VERSION 5.8 ;
BUSBITCHARS "[]" ;
DIVIDERCHAR "/" ;
UNITS
    DATABASE MICRONS 1000 ;
END UNITS

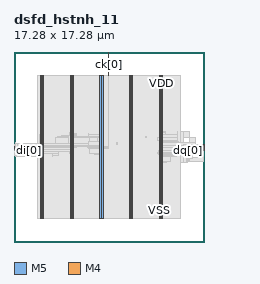
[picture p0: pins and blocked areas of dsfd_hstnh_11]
MACRO dsfd_hstnh_11
  FOREIGN dsfd_hstnh_11 0 0 ;
  CLASS BLOCK ;
  SIZE 17.28 BY 17.28 ;
  PIN ck[0]
    DIRECTION INPUT ;
    USE SIGNAL ;
    PORT
      LAYER M5 ;
        RECT  8.592 17.196 8.616 17.28 ;
    END
    PORT
      LAYER M5 ;
        RECT  8.592 15.143 8.616 17.232 ;
    END
  END ck[0]
  PIN di[0]
    DIRECTION INPUT ;
    USE SIGNAL ;
    PORT
      LAYER M4 ;
        RECT  0 8.352 0.084 8.376 ;
    END
  END di[0]
  PIN di[10]
    DIRECTION INPUT ;
    USE SIGNAL ;
    PORT
      LAYER M4 ;
        RECT  0 8.832 0.084 8.856 ;
    END
  END di[10]
  PIN di[1]
    DIRECTION INPUT ;
    USE SIGNAL ;
    PORT
      LAYER M4 ;
        RECT  0 8.4 0.084 8.424 ;
    END
  END di[1]
  PIN di[2]
    DIRECTION INPUT ;
    USE SIGNAL ;
    PORT
      LAYER M4 ;
        RECT  0 8.448 0.084 8.472 ;
    END
  END di[2]
  PIN di[3]
    DIRECTION INPUT ;
    USE SIGNAL ;
    PORT
      LAYER M4 ;
        RECT  0 8.496 0.084 8.52 ;
    END
  END di[3]
  PIN di[4]
    DIRECTION INPUT ;
    USE SIGNAL ;
    PORT
      LAYER M4 ;
        RECT  0 8.544 0.084 8.568 ;
    END
  END di[4]
  PIN di[5]
    DIRECTION INPUT ;
    USE SIGNAL ;
    PORT
      LAYER M4 ;
        RECT  0 8.592 0.084 8.616 ;
    END
  END di[5]
  PIN di[6]
    DIRECTION INPUT ;
    USE SIGNAL ;
    PORT
      LAYER M4 ;
        RECT  0 8.64 0.084 8.664 ;
    END
  END di[6]
  PIN di[7]
    DIRECTION INPUT ;
    USE SIGNAL ;
    PORT
      LAYER M4 ;
        RECT  0 8.688 0.084 8.712 ;
    END
  END di[7]
  PIN di[8]
    DIRECTION INPUT ;
    USE SIGNAL ;
    PORT
      LAYER M4 ;
        RECT  0 8.736 0.084 8.76 ;
    END
  END di[8]
  PIN di[9]
    DIRECTION INPUT ;
    USE SIGNAL ;
    PORT
      LAYER M4 ;
        RECT  0 8.784 0.084 8.808 ;
    END
  END di[9]
  PIN dq[0]
    DIRECTION OUTPUT ;
    USE SIGNAL ;
    PORT
      LAYER M4 ;
        RECT  17.196 8.352 17.28 8.376 ;
    END
  END dq[0]
  PIN dq[10]
    DIRECTION OUTPUT ;
    USE SIGNAL ;
    PORT
      LAYER M4 ;
        RECT  17.196 8.832 17.28 8.856 ;
    END
  END dq[10]
  PIN dq[1]
    DIRECTION OUTPUT ;
    USE SIGNAL ;
    PORT
      LAYER M4 ;
        RECT  17.196 8.4 17.28 8.424 ;
    END
  END dq[1]
  PIN dq[2]
    DIRECTION OUTPUT ;
    USE SIGNAL ;
    PORT
      LAYER M4 ;
        RECT  17.196 8.448 17.28 8.472 ;
    END
  END dq[2]
  PIN dq[3]
    DIRECTION OUTPUT ;
    USE SIGNAL ;
    PORT
      LAYER M4 ;
        RECT  17.196 8.496 17.28 8.52 ;
    END
  END dq[3]
  PIN dq[4]
    DIRECTION OUTPUT ;
    USE SIGNAL ;
    PORT
      LAYER M4 ;
        RECT  17.196 8.544 17.28 8.568 ;
    END
  END dq[4]
  PIN dq[5]
    DIRECTION OUTPUT ;
    USE SIGNAL ;
    PORT
      LAYER M4 ;
        RECT  17.196 8.592 17.28 8.616 ;
    END
  END dq[5]
  PIN dq[6]
    DIRECTION OUTPUT ;
    USE SIGNAL ;
    PORT
      LAYER M4 ;
        RECT  17.196 8.64 17.28 8.664 ;
    END
  END dq[6]
  PIN dq[7]
    DIRECTION OUTPUT ;
    USE SIGNAL ;
    PORT
      LAYER M4 ;
        RECT  17.196 8.688 17.28 8.712 ;
    END
  END dq[7]
  PIN dq[8]
    DIRECTION OUTPUT ;
    USE SIGNAL ;
    PORT
      LAYER M4 ;
        RECT  17.196 8.736 17.28 8.76 ;
    END
  END dq[8]
  PIN dq[9]
    DIRECTION OUTPUT ;
    USE SIGNAL ;
    PORT
      LAYER M4 ;
        RECT  17.196 8.784 17.28 8.808 ;
    END
  END dq[9]
  PIN VDD
    DIRECTION INOUT ;
    USE POWER ;
    PORT
      LAYER M5 ;
        RECT  13.392 2.151 13.512 15.129 ;
        RECT  10.692 2.151 10.812 15.129 ;
        RECT  7.992 2.151 8.112 15.129 ;
        RECT  5.292 2.151 5.412 15.129 ;
        RECT  2.592 2.151 2.712 15.129 ;
    END
  END VDD
  PIN VSS
    DIRECTION INOUT ;
    USE GROUND ;
    PORT
      LAYER M5 ;
        RECT  13.2 2.137 13.32 15.143 ;
        RECT  10.5 2.137 10.62 15.143 ;
        RECT  7.8 2.137 7.92 15.143 ;
        RECT  5.1 2.137 5.22 15.143 ;
        RECT  2.4 2.137 2.52 15.143 ;
    END
  END VSS
  # OT_OBS_CLOSED layer=M5 d_um=1.536 added=0
  OBS
    LAYER RVTN ;
     RECT  2.16 2.16 15.12 2.295 ;
     RECT  2.16 2.565 15.12 2.835 ;
     RECT  2.16 3.105 15.12 3.375 ;
     RECT  2.16 3.645 15.12 3.915 ;
     RECT  2.16 4.185 15.12 4.455 ;
     RECT  2.16 4.725 15.12 4.995 ;
     RECT  2.16 5.265 15.12 5.535 ;
     RECT  2.16 5.805 15.12 6.075 ;
     RECT  2.16 6.345 15.12 6.615 ;
     RECT  2.16 6.885 15.12 7.155 ;
     RECT  2.16 7.425 15.12 7.695 ;
     RECT  2.16 7.965 15.12 8.235 ;
     RECT  2.16 8.505 15.12 8.775 ;
     RECT  2.16 9.045 15.12 9.315 ;
     RECT  2.16 9.585 15.12 9.855 ;
     RECT  2.16 10.125 15.12 10.395 ;
     RECT  2.16 10.665 15.12 10.935 ;
     RECT  2.16 11.205 15.12 11.475 ;
     RECT  2.16 11.745 15.12 12.015 ;
     RECT  2.16 12.285 15.12 12.555 ;
     RECT  2.16 12.825 15.12 13.095 ;
     RECT  2.16 13.365 15.12 13.635 ;
     RECT  2.16 13.905 15.12 14.175 ;
     RECT  2.16 14.445 15.12 14.715 ;
     RECT  2.16 14.985 15.12 15.12 ;
    LAYER RVTP ;
     RECT  2.16 2.295 15.12 2.565 ;
     RECT  2.16 2.835 15.12 3.105 ;
     RECT  2.16 3.375 15.12 3.645 ;
     RECT  2.16 3.915 15.12 4.185 ;
     RECT  2.16 4.455 15.12 4.725 ;
     RECT  2.16 4.995 15.12 5.265 ;
     RECT  2.16 5.535 15.12 5.805 ;
     RECT  2.16 6.075 15.12 6.345 ;
     RECT  2.16 6.615 15.12 6.885 ;
     RECT  2.16 7.155 15.12 7.425 ;
     RECT  2.16 7.695 15.12 7.965 ;
     RECT  2.16 8.235 15.12 8.505 ;
     RECT  2.16 8.775 15.12 9.045 ;
     RECT  2.16 9.315 15.12 9.585 ;
     RECT  2.16 9.855 15.12 10.125 ;
     RECT  2.16 10.395 15.12 10.665 ;
     RECT  2.16 10.935 15.12 11.205 ;
     RECT  2.16 11.475 15.12 11.745 ;
     RECT  2.16 12.015 15.12 12.285 ;
     RECT  2.16 12.555 15.12 12.825 ;
     RECT  2.16 13.095 15.12 13.365 ;
     RECT  2.16 13.635 15.12 13.905 ;
     RECT  2.16 14.175 15.12 14.445 ;
     RECT  2.16 14.715 15.12 14.985 ;
    LAYER M1 ;
     RECT  2.16 2.151 15.12 15.129 ;
    LAYER M2 ;
     RECT  0.031 7.902 0.103 7.92 ;
     RECT  0.103 7.902 0.139 7.956 ;
     RECT  0.139 7.902 0.175 8.46 ;
     RECT  0.175 7.776 2.16 8.46 ;
     RECT  2.16 2.151 15.12 15.129 ;
     RECT  15.12 7.236 15.431 10.044 ;
     RECT  15.431 7.236 15.755 8.532 ;
     RECT  15.755 7.326 15.899 8.532 ;
     RECT  15.899 7.326 15.971 8.46 ;
     RECT  15.431 9.486 15.971 10.044 ;
     RECT  15.971 8.406 16.007 8.46 ;
     RECT  16.007 8.442 16.079 8.46 ;
     RECT  15.971 9.486 16.511 9.504 ;
     RECT  15.971 7.326 17.231 7.65 ;
     RECT  17.231 7.326 17.267 7.344 ;
     RECT  17.095 8.586 17.267 8.604 ;
    LAYER M3 ;
     RECT  2.415 2.143 2.505 2.413 ;
     RECT  5.115 2.143 5.205 2.413 ;
     RECT  7.815 2.143 7.905 2.413 ;
     RECT  10.515 2.143 10.605 2.413 ;
     RECT  13.215 2.143 13.305 2.413 ;
     RECT  13.215 2.413 13.497 7.195 ;
     RECT  13.215 7.195 13.878 7.321 ;
     RECT  15.732 7.231 15.75 7.591 ;
     RECT  17.244 7.321 17.262 7.627 ;
     RECT  13.215 7.321 14.274 7.735 ;
     RECT  3.492 7.771 3.51 7.861 ;
     RECT  13.215 7.735 14.778 7.889 ;
     RECT  0.18 7.771 0.198 7.897 ;
     RECT  13.215 7.889 14.382 7.933 ;
     RECT  7.815 2.413 8.097 7.969 ;
     RECT  2.415 2.413 2.697 8.041 ;
     RECT  3.492 7.861 4.086 8.041 ;
     RECT  5.115 2.413 5.397 8.041 ;
     RECT  7.308 7.969 8.097 8.041 ;
     RECT  13.176 7.933 14.382 8.041 ;
     RECT  0.036 7.897 0.198 8.059 ;
     RECT  17.208 7.627 17.262 8.155 ;
     RECT  13.068 8.041 14.382 8.159 ;
     RECT  0.036 8.059 0.27 8.189 ;
     RECT  2.415 8.041 4.086 8.203 ;
     RECT  5.004 8.041 5.397 8.203 ;
     RECT  0.108 8.189 0.27 8.285 ;
     RECT  15.732 7.591 16.254 8.311 ;
     RECT  13.176 8.159 14.382 8.339 ;
     RECT  2.415 8.203 5.397 8.395 ;
     RECT  6.876 8.041 8.097 8.473 ;
     RECT  6.84 8.473 8.097 8.509 ;
     RECT  0.144 8.285 0.27 8.525 ;
     RECT  6.84 8.509 8.586 8.545 ;
     RECT  2.376 8.395 5.397 8.581 ;
     RECT  6.804 8.545 8.586 8.581 ;
     RECT  2.376 8.581 5.706 8.587 ;
     RECT  17.1 8.155 17.262 8.609 ;
     RECT  17.1 8.609 17.118 8.621 ;
     RECT  2.304 8.587 5.706 8.635 ;
     RECT  13.215 8.339 14.382 8.635 ;
     RECT  15.408 8.311 16.254 8.635 ;
     RECT  6.66 8.581 8.586 8.699 ;
     RECT  2.232 8.635 5.706 8.707 ;
     RECT  6.66 8.699 6.822 8.707 ;
     RECT  13.215 8.635 16.254 8.731 ;
     RECT  2.232 8.707 6.822 8.807 ;
     RECT  2.304 8.807 6.822 8.969 ;
     RECT  9.36 8.851 9.45 8.969 ;
     RECT  0.144 8.525 0.162 9.005 ;
     RECT  9.36 8.969 9.378 9.005 ;
     RECT  13.215 8.731 16.506 9.041 ;
     RECT  13.215 9.041 14.994 9.113 ;
     RECT  13.215 9.113 14.85 9.211 ;
     RECT  3.78 8.969 6.822 9.481 ;
     RECT  7.56 8.699 8.406 9.481 ;
     RECT  3.78 9.481 8.406 9.509 ;
     RECT  13.032 9.211 14.85 9.509 ;
     RECT  15.948 9.041 16.506 9.509 ;
     RECT  3.96 9.509 8.406 9.517 ;
     RECT  3.96 9.517 8.478 9.617 ;
     RECT  11.988 9.517 12.006 9.617 ;
     RECT  4.32 9.617 5.67 9.689 ;
     RECT  2.304 8.969 2.697 9.779 ;
     RECT  6.768 9.617 8.097 9.779 ;
     RECT  13.215 9.509 14.85 9.779 ;
     RECT  5.004 9.689 5.67 9.815 ;
     RECT  7.56 9.779 8.097 9.815 ;
     RECT  5.076 9.815 5.67 9.851 ;
     RECT  6.768 9.779 6.786 9.887 ;
     RECT  5.076 9.851 5.397 9.959 ;
     RECT  13.215 9.779 13.806 9.959 ;
     RECT  13.215 9.959 13.77 10.049 ;
     RECT  15.948 9.509 15.966 10.049 ;
     RECT  14.832 9.779 14.85 10.085 ;
     RECT  2.415 9.779 2.697 14.867 ;
     RECT  5.115 9.959 5.397 14.867 ;
     RECT  7.815 9.815 8.097 14.867 ;
     RECT  10.515 2.413 10.797 14.867 ;
     RECT  13.215 10.049 13.497 14.867 ;
     RECT  2.415 14.867 2.505 15.137 ;
     RECT  5.115 14.867 5.205 15.137 ;
     RECT  7.815 14.867 7.905 15.137 ;
     RECT  10.515 14.867 10.605 15.137 ;
     RECT  13.215 14.867 13.305 15.137 ;
    LAYER M4 ;
     RECT  0.025 8.16 0.06 8.184 ;
     RECT  0.06 8.16 0.133 8.856 ;
     RECT  0.133 8.16 0.169 9 ;
     RECT  0.169 8.064 0.281 9 ;
     RECT  0.281 8.4 2.408 9 ;
     RECT  2.408 2.148 2.512 15.132 ;
     RECT  2.512 2.418 2.704 14.862 ;
     RECT  4.949 9.696 4.981 9.72 ;
     RECT  4.981 8.976 5.108 9.72 ;
     RECT  5.108 2.148 5.212 15.132 ;
     RECT  5.212 2.418 5.404 14.862 ;
     RECT  5.404 8.736 6.793 9 ;
     RECT  6.793 8.736 7.808 9.096 ;
     RECT  7.808 2.148 7.912 15.132 ;
     RECT  7.912 2.418 8.104 14.862 ;
     RECT  8.104 8.736 8.627 8.76 ;
     RECT  10.508 2.148 10.612 15.132 ;
     RECT  10.612 2.418 10.804 14.862 ;
     RECT  13.208 2.148 13.312 15.132 ;
     RECT  13.312 2.418 13.504 14.862 ;
     RECT  14.965 8.64 15.397 8.664 ;
     RECT  15.397 8.496 15.721 8.856 ;
     RECT  15.721 8.4 17.089 8.856 ;
     RECT  17.089 8.16 17.237 8.856 ;
     RECT  17.237 8.352 17.244 8.856 ;
    LAYER M5 ;
     RECT  2.4 2.137 2.52 2.151 ;
     RECT  5.1 2.137 5.22 2.151 ;
     RECT  7.8 2.137 7.92 2.151 ;
     RECT  10.5 2.137 10.62 2.151 ;
     RECT  13.2 2.137 13.32 2.151 ;
     RECT  7.8 2.151 8.112 8.725 ;
     RECT  0.144 8.773 0.168 8.963 ;
     RECT  5.1 2.151 5.412 8.965 ;
     RECT  4.992 8.965 5.412 9.731 ;
     RECT  2.4 2.151 2.712 15.129 ;
     RECT  5.1 9.731 5.412 15.129 ;
     RECT  10.5 2.151 10.812 15.129 ;
     RECT  13.2 2.151 13.512 15.129 ;
     RECT  2.4 15.129 2.52 15.143 ;
     RECT  5.1 15.129 5.22 15.143 ;
     RECT  7.8 8.725 8.616 15.143 ;
     RECT  10.5 15.129 10.62 15.143 ;
     RECT  13.2 15.129 13.32 15.143 ;
  END
END dsfd_hstnh_11
END LIBRARY
